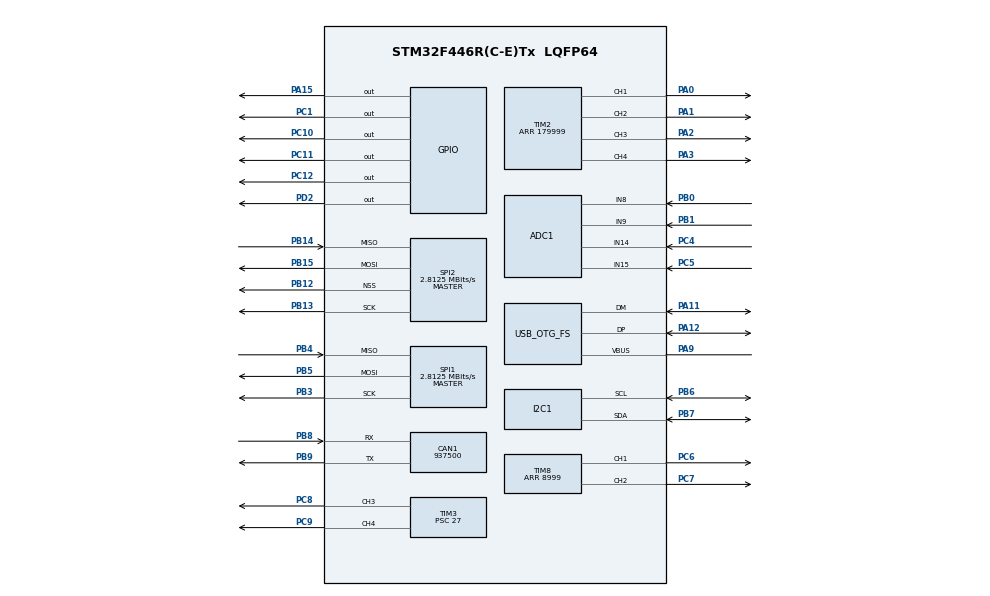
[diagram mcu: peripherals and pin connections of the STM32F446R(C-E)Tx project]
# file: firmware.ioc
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ADC1.Channel-0\#ChannelRegularConversion=ADC_CHANNEL_14
ADC1.NbrOfConversionFlag=1
ADC1.Rank-0\#ChannelRegularConversion=1
ADC1.SamplingTime-0\#ChannelRegularConversion=ADC_SAMPLETIME_3CYCLES
ADC1.master=1
CAN1.BS1=CAN_BS1_1TQ
CAN1.BS2=CAN_BS2_1TQ
CAN1.CalculateBaudRate=937500
CAN1.CalculateTimeBit=1066
CAN1.CalculateTimeQuantum=355.55555555555554
Mcu.Family=STM32F4
Mcu.Name=STM32F446R(C-E)Tx
Mcu.Package=LQFP64
NVIC.OTG_FS_IRQn=true\:0\:0\:false\:false\:true\:false\:true\:true
NVIC.PriorityGroup=NVIC_PRIORITYGROUP_4
PA0-WKUP.Signal=S_TIM2_CH1_ETR
PA1.Signal=S_TIM2_CH2
PA11.Mode=Device_Only
PA11.Signal=USB_OTG_FS_DM
PA12.Mode=Device_Only
PA12.Signal=USB_OTG_FS_DP
PA13.Mode=Serial_Wire
PA13.Signal=SYS_JTMS-SWDIO
PA14.Mode=Serial_Wire
PA14.Signal=SYS_JTCK-SWCLK
PA15.Signal=GPIO_Output
PA2.Signal=S_TIM2_CH3
PA3.Signal=S_TIM2_CH4
PA9.Mode=Activate_VBUS
PA9.Signal=USB_OTG_FS_VBUS
PB0.Signal=ADCx_IN8
PB1.Signal=ADCx_IN9
PB12.Mode=NSS_Signal_Hard_Output
PB12.Signal=SPI2_NSS
PB13.Mode=Full_Duplex_Master
PB13.Signal=SPI2_SCK
PB14.Mode=Full_Duplex_Master
PB14.Signal=SPI2_MISO
PB15.Mode=Full_Duplex_Master
PB15.Signal=SPI2_MOSI
PB3.Mode=Full_Duplex_Master
PB3.Signal=SPI1_SCK
PB4.Mode=Full_Duplex_Master
PB4.Signal=SPI1_MISO
PB5.Mode=Full_Duplex_Master
PB5.Signal=SPI1_MOSI
PB6.Mode=I2C
PB6.Signal=I2C1_SCL
PB7.Mode=I2C
PB7.Signal=I2C1_SDA
PB8.Mode=CAN_Activate
PB8.Signal=CAN1_RX
PB9.Mode=CAN_Activate
PB9.Signal=CAN1_TX
PC1.Signal=GPIO_Output
PC10.Signal=GPIO_Output
PC11.Signal=GPIO_Output
PC12.Signal=GPIO_Output
PC4.Signal=ADCx_IN14
PC5.Signal=ADCx_IN15
PC6.Signal=S_TIM8_CH1
PC7.Signal=S_TIM8_CH2
PC8.Signal=S_TIM3_CH3
PC9.Signal=S_TIM3_CH4
PD2.Signal=GPIO_Output
PH0-OSC_IN.Mode=HSE-External-Oscillator
PH0-OSC_IN.Signal=RCC_OSC_IN
PH1-OSC_OUT.Mode=HSE-External-Oscillator
PH1-OSC_OUT.Signal=RCC_OSC_OUT
ProjectManager.HeapSize=0x800
ProjectManager.StackSize=0x1000
ProjectManager.TargetToolchain=CMake
RCC.AHBFreq_Value=180000000
RCC.APB1CLKDivider=RCC_HCLK_DIV4
RCC.APB1Freq_Value=45000000
RCC.APB1TimFreq_Value=90000000
RCC.APB2CLKDivider=RCC_HCLK_DIV4
RCC.APB2Freq_Value=45000000
RCC.APB2TimFreq_Value=90000000
RCC.CortexFreq_Value=180000000
RCC.HCLKFreq_Value=180000000
RCC.HSE_VALUE=16000000
RCC.PLLM=8
RCC.PLLN=180
RCC.PLLSAIP=RCC_PLLSAIP_DIV4
RCC.SYSCLKFreq_VALUE=180000000
RCC.SYSCLKSource=RCC_SYSCLKSOURCE_PLLCLK
RCC.USBCLockSelection=RCC_CLK48CLKSOURCE_PLLSAIP
RCC.USBFreq_Value=48000000
RCC.VCOOutputFreq_Value=360000000
SH.ADCx_IN14.0=ADC1_IN14,IN14
SH.ADCx_IN15.0=ADC1_IN15,IN15
SH.ADCx_IN8.0=ADC1_IN8,IN8
SH.ADCx_IN9.0=ADC1_IN9,IN9
SH.S_TIM2_CH1_ETR.0=TIM2_CH1,PWM Generation1 CH1
SH.S_TIM2_CH2.0=TIM2_CH2,PWM Generation2 CH2
SH.S_TIM2_CH3.0=TIM2_CH3,PWM Generation3 CH3
SH.S_TIM2_CH4.0=TIM2_CH4,PWM Generation4 CH4
SH.S_TIM3_CH3.0=TIM3_CH3,PWM Generation3 CH3
SH.S_TIM3_CH4.0=TIM3_CH4,PWM Generation4 CH4
SH.S_TIM8_CH1.0=TIM8_CH1,PWM Generation1 CH1
SH.S_TIM8_CH2.0=TIM8_CH2,PWM Generation2 CH2
SPI1.BaudRatePrescaler=SPI_BAUDRATEPRESCALER_16
SPI1.CLKPhase=SPI_PHASE_2EDGE
SPI1.CalculateBaudRate=2.8125 MBits/s
SPI1.DataSize=SPI_DATASIZE_16BIT
SPI1.Direction=SPI_DIRECTION_2LINES
SPI1.Mode=SPI_MODE_MASTER
SPI1.VirtualType=VM_MASTER
SPI2.BaudRatePrescaler=SPI_BAUDRATEPRESCALER_16
SPI2.CLKPhase=SPI_PHASE_2EDGE
SPI2.CalculateBaudRate=2.8125 MBits/s
SPI2.DataSize=SPI_DATASIZE_16BIT
SPI2.Direction=SPI_DIRECTION_2LINES
SPI2.Mode=SPI_MODE_MASTER
SPI2.VirtualNSS=VM_NSSHARD
SPI2.VirtualType=VM_MASTER
TIM2.Channel-PWM\ Generation1\ CH1=TIM_CHANNEL_1
TIM2.Channel-PWM\ Generation2\ CH2=TIM_CHANNEL_2
TIM2.Channel-PWM\ Generation3\ CH3=TIM_CHANNEL_3
TIM2.Channel-PWM\ Generation4\ CH4=TIM_CHANNEL_4
TIM2.Period=179999
TIM3.AutoReloadPreload=TIM_AUTORELOAD_PRELOAD_ENABLE
TIM3.Channel-PWM\ Generation3\ CH3=TIM_CHANNEL_3
TIM3.Channel-PWM\ Generation4\ CH4=TIM_CHANNEL_4
TIM3.Period=64285
TIM3.Prescaler=27
TIM8.AutoReloadPreload=TIM_AUTORELOAD_PRELOAD_ENABLE
TIM8.Channel-PWM\ Generation1\ CH1=TIM_CHANNEL_1
TIM8.Channel-PWM\ Generation2\ CH2=TIM_CHANNEL_2
TIM8.Period=8999
TIM8.Pulse-PWM\ Generation1\ CH1=4500
USB_DEVICE.CLASS_NAME_FS=CDC
USB_DEVICE.VirtualMode-CDC_FS=Cdc
USB_DEVICE.VirtualModeFS=Cdc_FS
USB_OTG_FS.VirtualMode=Device_Only
VP_TIM2_VS_ClockSourceINT.Mode=Internal
VP_TIM3_VS_ClockSourceINT.Mode=Internal
VP_TIM8_VS_ClockSourceINT.Mode=Internal
VP_USB_DEVICE_VS_USB_DEVICE_CDC_FS.Mode=CDC_FS
board=custom

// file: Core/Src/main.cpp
/* USER CODE BEGIN Header */
/**
  ******************************************************************************
  * @file           : main.c
  * @brief          : Main program body
  ******************************************************************************
  * @attention
  *
  * Copyright (c) 2026 STMicroelectronics.
  * All rights reserved.
  *
  * This software is licensed under terms that can be found in the LICENSE file
  * in the root directory of this software component.
  * If no LICENSE file comes with this software, it is provided AS-IS.
  *
  ******************************************************************************
  */
/* USER CODE END Header */
#include "main.h"
#include "adc.h"
#include "can.h"
#include "i2c.h"
#include "spi.h"
#include "tim.h"
#include "usb_device.h"
#include "gpio.h"

/* USER CODE BEGIN Includes */
#include "core.hpp"
/* USER CODE END Includes */

#ifdef __cplusplus
extern "C" {
#endif

void SystemClock_Config(void);

#ifdef __cplusplus
}
#endif

int main(void)
{

  /* MCU Configuration--------------------------------------------------------*/

  /* Reset of all peripherals, Initializes the Flash interface and the Systick. */
  HAL_Init();

  /* Configure the system clock */
  SystemClock_Config();

  /* Initialize all configured peripherals */
  MX_GPIO_Init();
  MX_ADC1_Init();
  MX_CAN1_Init();
  MX_I2C1_Init();
  MX_SPI1_Init();
  MX_SPI2_Init();
  MX_TIM2_Init();
  MX_TIM3_Init();
  MX_TIM8_Init();
  MX_USB_DEVICE_Init();
  /* USER CODE BEGIN 2 */
  core_init();
  /* USER CODE END 2 */

  /* Infinite loop */
  while (1)
  {

    /* USER CODE BEGIN 3 */
    core_update();
  }
  /* USER CODE END 3 */
}

void SystemClock_Config(void)
{
  RCC_OscInitTypeDef RCC_OscInitStruct = {0};
  RCC_ClkInitTypeDef RCC_ClkInitStruct = {0};

  /** Configure the main internal regulator output voltage
  */
  __HAL_RCC_PWR_CLK_ENABLE();
  __HAL_PWR_VOLTAGESCALING_CONFIG(PWR_REGULATOR_VOLTAGE_SCALE1);

  /** Initializes the RCC Oscillators according to the specified parameters
  * in the RCC_OscInitTypeDef structure.
  */
  RCC_OscInitStruct.OscillatorType = RCC_OSCILLATORTYPE_HSE;
  RCC_OscInitStruct.HSEState = RCC_HSE_ON;
  RCC_OscInitStruct.PLL.PLLState = RCC_PLL_ON;
  RCC_OscInitStruct.PLL.PLLSource = RCC_PLLSOURCE_HSE;
  RCC_OscInitStruct.PLL.PLLM = 8;
  RCC_OscInitStruct.PLL.PLLN = 180;
  RCC_OscInitStruct.PLL.PLLP = RCC_PLLP_DIV2;
  RCC_OscInitStruct.PLL.PLLQ = 2;
  RCC_OscInitStruct.PLL.PLLR = 2;
  if (HAL_RCC_OscConfig(&RCC_OscInitStruct) != HAL_OK)
  {
    Error_Handler();
  }

  /** Activate the Over-Drive mode
  */
  if (HAL_PWREx_EnableOverDrive() != HAL_OK)
  {
    Error_Handler();
  }

  /** Initializes the CPU, AHB and APB buses clocks
  */
  RCC_ClkInitStruct.ClockType = RCC_CLOCKTYPE_HCLK|RCC_CLOCKTYPE_SYSCLK
                              |RCC_CLOCKTYPE_PCLK1|RCC_CLOCKTYPE_PCLK2;
  RCC_ClkInitStruct.SYSCLKSource = RCC_SYSCLKSOURCE_PLLCLK;
  RCC_ClkInitStruct.AHBCLKDivider = RCC_SYSCLK_DIV1;
  RCC_ClkInitStruct.APB1CLKDivider = RCC_HCLK_DIV4;
  RCC_ClkInitStruct.APB2CLKDivider = RCC_HCLK_DIV2;

  if (HAL_RCC_ClockConfig(&RCC_ClkInitStruct, FLASH_LATENCY_5) != HAL_OK)
  {
    Error_Handler();
  }
}

void Error_Handler(void)
{
  __disable_irq();
  while (1)
  {
  }
}
